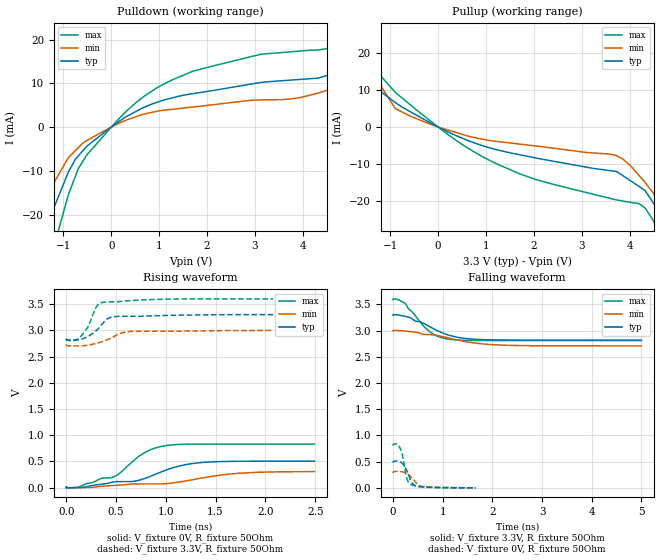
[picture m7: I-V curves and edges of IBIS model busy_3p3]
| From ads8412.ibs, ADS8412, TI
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|   busy_3p3 Model
[Model]   busy_3p3
Model_type   Output
Polarity   Non-Inverting
Vmeas = 1.65
Vref = 1.65
Cref = 20pF
Rref = 50
|   typ   min   max
|   (nom PVT)   (fast PVT)   (slow PVT)
|C_comp from frequency sweep method (F=1MHz)
|C_comp   1.038e-12   9.792e-13   1.098e-12
|ON state : BUFFER OUTPUT TURNED HIGH
|C_comp   1.038e-12   9.792e-13   1.098e-12
|OFF state: BUFFER OUTPUT TURNED LOW
|C_comp   1.100e-12   1.043e-12   1.154e-12
|C_comp from LC tank measurement(L=1nH)
|Resonant Frequency(Hz)   9.020e+09   9.370e+09   8.550e+09
C_comp   3.116e-13   2.888e-13   3.468e-13
|ON state : BUFFER OUTPUT TURNED HIGH
|Resonant Frequency(Hz)   8.970e+09   9.360e+09   8.460e+09
|C_comp   3.151e-13   2.894e-13   3.543e-13
|OFF state: BUFFER OUTPUT TURNED LOW
|Resonant Frequency(Hz)   9.020e+09   9.370e+09   8.550e+09
|C_comp   3.116e-13   2.888e-13   3.468e-13
| Where nom  PVT is Nominal Process, 3.3V, 40C
|   Fast PVT is Strong Process,  3.6V, -40C
|   Slow PVT is Weak Process,   3V, 100C
[Voltage Range]   3.3   3   3.6
|Ambient Temperature   25   85   -40
|Junction Temperature
[Temperature Range]   40   100   -40
[Pullup Reference]   3.3   3   3.6
[Pulldown Reference]   0   0   0
[Power Clamp Reference]   3.3   3   3.6
[GND Clamp Reference]   0   0   0
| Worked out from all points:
|   slope of the pulldown table from 0 to 0.495 V, typ, clamps not added: 143 ohm
|   slope of the pullup table from 0 to 0.495 V, typ, clamps not added: 168 ohm
|   falling waveform, V_fixture 3.3V, R_fixture 50Ohm: 20-80 % time 704ps typ, 1.06ns min, 460ps max; typ from 3.3 V to 2.82 V
|   rising waveform, V_fixture 0V, R_fixture 50Ohm: 20-80 % time 663ps typ, 959ps min, 447ps max; typ from 0 V to 0.505 V
|   rising waveform, V_fixture 3.3V, R_fixture 50Ohm: 20-80 % time 158ps typ, 214ps min, 120ps max; typ from 2.82 V to 3.3 V
|   falling waveform, V_fixture 0V, R_fixture 50Ohm: 20-80 % time 143ps typ, 191ps min, 104ps max; typ from 0.505 V to 0.001 V
[Pulldown]
|   Voltage   I(typ)   I(min)   I(max)
-3.3V     -645.6mA   -463.2mA   -985.7mA
-1.647V   -30.6mA    -24.52mA   -59.7mA
-1.566V   -28.41mA   -19.67mA   -41.81mA
-897.6mV  -10.29mA   -7.02mA    -15.5mA
-591mV    -5.353mA   -3.606mA   -7.764mA
478.8mV   3.358mA    2.221mA    5.234mA
1.696V    7.62mA     4.565mA    12.73mA
4.503V    11.8mA     8.401mA    17.92mA
4.749V    13.64mA    12.39mA    19.47mA
4.911V    14.85mA    40.7mA     20.48mA
5.112V    44.82mA    95.45mA    21.75mA
6.6V      638.9mA    549.3mA    800.4mA
[Pullup]
|   Voltage   I(typ)   I(min)   I(max)
-3.3V     638.9mA    457.7mA    976.6mA
-2.099V   149.3mA    93.8mA     276.7mA
-1.769V   32.9mA     22.73mA    101.1mA
-1.63V    14.37mA    19.91mA    37.13mA
-1.544V   12.91mA    18.17mA    18.77mA
-897mV    6.632mA    5.016mA    9.388mA
478.8mV   -2.866mA   -1.875mA   -4.502mA
1.706V    -7.485mA   -4.598mA   -12.64mA
3.855V    -13.11mA   -8.632mA   -19.94mA
4.503V    -20.72mA   -18.03mA   -25.49mA
4.776V    -27.92mA   -26.68mA   -34.18mA
6.6V      -645.6mA   -554.3mA   -809.3mA
[Ramp]
R_load = 50
|   typ   min   max
dV/dt_r   0.303298/6.62577e-10   0.184835/9.6224e-10   0.498804/4.48607e-10
dV/dt_f   0.289442/7.03417e-10   0.175769/1.05805e-09   0.474125/4.60541e-10
[Falling Waveform]
V_fixture = 3.3V
V_fixture_min = 3V
V_fixture_max = 3.6V
R_fixture = 50Ohm
|   Time   V(typ)   V(min)   V(max)
0s        3.3V       3V         3.6V
237ps     3.27V      2.991V     3.523V
300ps     3.259V     2.985V     3.427V
603ps     3.142V     2.93V      3.097V
751ps     3.068V     2.922V     2.968V
909ps     2.99V      2.903V     2.886V
1.105ns   2.917V     2.861V     2.838V
1.51ns    2.845V     2.781V     2.813V
2.204ns   2.82V      2.722V     2.81V
4.999ns   2.818V     2.707V     2.81V
[Rising Waveform]
V_fixture = 0V
V_fixture_min = 0V
V_fixture_max = 0V
R_fixture = 50Ohm
|   Time   V(typ)   V(min)   V(max)
0s        1.364nV    2.286nV    1.294nV
121ps     1.722mV    -316.7uV   9.811mV
348ps     64.17mV    24.84mV    174.1mV
486ps     112.3mV    43.04mV    211.6mV
776ps     166.6mV    71.45mV    655.8mV
982ps     320.9mV    74.66mV    796.1mV
1.193ns   437.5mV    125.9mV    828.1mV
1.435ns   489.5mV    208.3mV    831.8mV
1.921ns   504.8mV    293.4mV    831.3mV
2.493ns   505.4mV    306.9mV    831.3mV
[Rising Waveform]
V_fixture = 3.3V
V_fixture_min = 3V
V_fixture_max = 3.6V
R_fixture = 50Ohm
|   Time   V(typ)   V(min)   V(max)
0s        2.818V     2.707V     2.81V
83ps      2.812V     2.704V     2.809V
144ps     2.826V     2.704V     2.88V
217ps     2.882V     2.716V     3.065V
296ps     2.987V     2.748V     3.427V
352ps     3.101V     2.779V     3.526V
452ps     3.251V     2.855V     3.544V
556ps     3.267V     2.95V      3.553V
645ps     3.269V     2.979V     3.567V
2.078ns   3.3V       2.999V     3.6V
[Falling Waveform]
V_fixture = 0V
V_fixture_min = 0V
V_fixture_max = 0V
R_fixture = 50Ohm
|   Time   V(typ)   V(min)   V(max)
0s        505.5mV    308.1mV    831.3mV
91ps      511.6mV    313.9mV    826.9mV
140ps     498.3mV    312.2mV    758.3mV
194ps     457mV      303.9mV    597.9mV
246ps     387.1mV    286.3mV    313.4mV
284ps     313.2mV    266.7mV    157.8mV
349ps     150.9mV    218.9mV    71.12mV
425ps     54.39mV    140mV      39.37mV
602ps     20.89mV    22.7mV     13.9mV
1.662ns   620.8uV    1.684mV    90.47uV
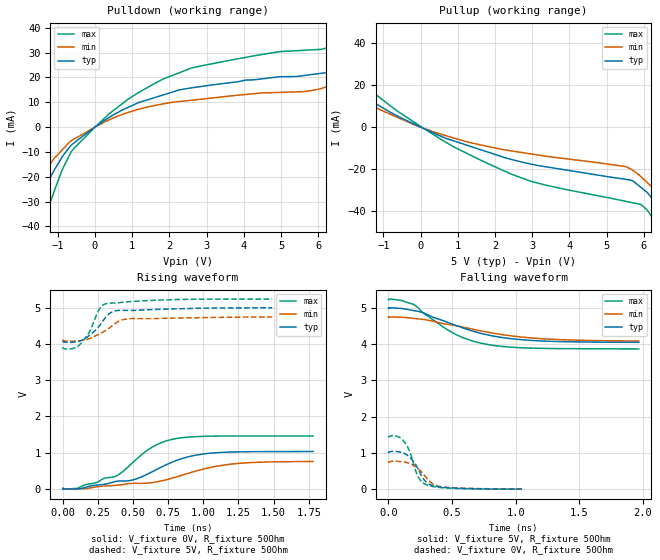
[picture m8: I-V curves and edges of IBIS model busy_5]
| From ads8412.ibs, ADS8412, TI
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|   busy_5 Model
[Model]   busy_5
Model_type   Output
Polarity   Non-Inverting
Vmeas = 2.5
Vref = 2.5
Cref = 20pF
Rref = 50
|   typ   min   max
|   (nom PVT)   (fast PVT)   (slow PVT)
|C_comp from frequency sweep method (F=1MHz)
|C_comp   9.492e-13   9.041e-13   9.984e-13
|ON state : BUFFER OUTPUT TURNED HIGH
|C_comp   9.492e-13   9.041e-13   9.984e-13
|OFF state: BUFFER OUTPUT TURNED LOW
|C_comp   1.017e-12   9.874e-13   1.044e-12
|C_comp from LC tank measurement(L=1nH)
|Resonant Frequency(Hz)   9.050e+09   9.410e+09   8.540e+09
C_comp   3.096e-13   2.863e-13   3.477e-13
|ON state : BUFFER OUTPUT TURNED HIGH
|Resonant Frequency(Hz)   8.940e+09   9.320e+09   8.390e+09
|C_comp   3.172e-13   2.919e-13   3.602e-13
|OFF state: BUFFER OUTPUT TURNED LOW
|Resonant Frequency(Hz)   9.050e+09   9.410e+09   8.540e+09
|C_comp   3.096e-13   2.863e-13   3.477e-13
| Where nom  PVT is Nominal Process, 5V, 40C
|   Fast PVT is Strong Process,  5.25V, -40C
|   Slow PVT is Weak Process,   4.75V, 100C
[Voltage Range]   5   4.75   5.25
|Ambient Temperature   25   85   -40
|Junction Temperature
[Temperature Range]   40   100   -40
[Pullup Reference]   5   4.75   5.25
[Pulldown Reference]   0   0   0
[Power Clamp Reference]   5   4.75   5.25
[GND Clamp Reference]   0   0   0
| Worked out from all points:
|   slope of the pulldown table from 0 to 0.75 V, typ, clamps not added: 107 ohm
|   slope of the pullup table from 0 to 0.75 V, typ, clamps not added: 131 ohm
|   falling waveform, V_fixture 5V, R_fixture 50Ohm: 20-80 % time 490ps typ, 615ps min, 371ps max; typ from 5 V to 4.05 V
|   rising waveform, V_fixture 0V, R_fixture 50Ohm: 20-80 % time 465ps typ, 587ps min, 349ps max; typ from 0 V to 1.03 V
|   rising waveform, V_fixture 5V, R_fixture 50Ohm: 20-80 % time 132ps typ, 163ps min, 106ps max; typ from 4.05 V to 5 V
|   falling waveform, V_fixture 0V, R_fixture 50Ohm: 20-80 % time 111ps typ, 128ps min, 91.7ps max; typ from 1.03 V to 0.003 V
[Pulldown]
|   Voltage   I(typ)   I(min)   I(max)
-5V       -1.352A    -999.9mA   -1.995A
-1.837V   -71.4mA    -41.97mA   -144.5mA
-1.776V   -54.3mA    -30.09mA   -118.2mA
-1.627V   -35.97mA   -25.93mA   -54.24mA
-1.31V    -23.31mA   -17.05mA   -34.67mA
-640mV    -7.275mA   -5.522mA   -10mA
924mV     8.182mA    6.075mA    11.61mA
2.594V    15.82mA    10.83mA    23.82mA
6.45V     22.78mA    17.29mA    32.94mA
6.575V    23.38mA    26.92mA    33.81mA
6.775V    38.27mA    71.8mA     39.73mA
10V       1.348A     1.076A     1.833A
[Pullup]
|   Voltage   I(typ)   I(min)   I(max)
-5V       1.348A     996.7mA    1.981A
-1.925V   83.92mA    49.15mA    182.4mA
-1.811V   52.11mA    27.18mA    117.5mA
-1.762V   38.4mA     17.72mA    96.41mA
-1.7V     20.99mA    16.7mA     69.55mA
-1.601V   18.81mA    15.1mA     26.95mA
-1.307V   12.34mA    10.31mA    16.87mA
2.94V     -17.5mA    -12.69mA   -25.64mA
5.629V    -25.15mA   -19.74mA   -35.73mA
6.36V     -36.89mA   -30.88mA   -47.08mA
6.805V    -60.94mA   -89.1mA    -67.44mA
10V       -1.352A    -1.079A    -1.847A
[Ramp]
R_load = 50
|   typ   min   max
dV/dt_r   0.620282/4.65245e-10   0.456871/5.9081e-10   0.87779/3.49751e-10
dV/dt_f   0.568783/4.90722e-10   0.399533/6.25727e-10   0.822014/3.69981e-10
[Falling Waveform]
V_fixture = 5V
V_fixture_min = 4.75V
V_fixture_max = 5.25V
R_fixture = 50Ohm
|   Time   V(typ)   V(min)   V(max)
0s        5V         4.75V      5.239V
93ps      4.989V     4.745V     5.215V
199ps     4.929V     4.713V     5.095V
273ps     4.868V     4.685V     4.865V
509ps     4.547V     4.527V     4.308V
656ps     4.369V     4.421V     4.094V
757ps     4.275V     4.348V     4.007V
921ps     4.172V     4.251V     3.931V
1.186ns   4.093V     4.158V     3.888V
1.966ns   4.054V     4.09V      3.87V
[Rising Waveform]
V_fixture = 0V
V_fixture_min = 0V
V_fixture_max = 0V
R_fixture = 50Ohm
|   Time   V(typ)   V(min)   V(max)
0s        1.868nV    2.766nV    1.738nV
104ps     5.649mV    1.528mV    18.48mV
296ps     129.9mV    81.26mV    296.3mV
377ps     209.6mV    100.5mV    351.9mV
496ps     247.6mV    155.2mV    724.5mV
610ps     424mV      164.7mV    1.09V
763ps     716.1mV    282.8mV    1.356V
944ps     931.4mV    491.7mV    1.443V
1.189ns   1.018V     682.1mV    1.462V
1.781ns   1.033V     758.7mV    1.463V
[Rising Waveform]
V_fixture = 5V
V_fixture_min = 4.75V
V_fixture_max = 5.25V
R_fixture = 50Ohm
|   Time   V(typ)   V(min)   V(max)
0s        4.052V     4.084V     3.869V
72ps      4.048V     4.078V     3.876V
124ps     4.084V     4.091V     3.993V
188ps     4.233V     4.147V     4.321V
262ps     4.507V     4.281V     4.971V
304ps     4.729V     4.37V      5.107V
357ps     4.893V     4.521V     5.129V
418ps     4.927V     4.657V     5.146V
477ps     4.926V     4.699V     5.168V
1.49ns    4.998V     4.746V     5.238V
[Falling Waveform]
V_fixture = 0V
V_fixture_min = 0V
V_fixture_max = 0V
R_fixture = 50Ohm
|   Time   V(typ)   V(min)   V(max)
0s        1.034V     761.5mV    1.463V
80ps      1.034V     766.9mV    1.445V
124ps     990.3mV    750.5mV    1.309V
167ps     883.5mV    709.7mV    1.038V
235ps     541.3mV    560.7mV    334mV
263ps     353.5mV    464.1mV    198.4mV
300ps     185.4mV    307.2mV    120.4mV
359ps     89.31mV    126.5mV    67.26mV
446ps     47.64mV    54.82mV    35.1mV
1.047ns   3.253mV    5.421mV    1.399mV
